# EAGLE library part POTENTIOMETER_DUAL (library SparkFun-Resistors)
Potentiometer (Pot) Dual-Gang Three-terminal potentiometers, with an adjustable wiper and two adjustable resistors. A pot can be used to create a configurable voltage divider, or as a variable resistor. This is a dua-gang pot - it includes two separate circuits, both controlled by one wiper. Variants PTH-12MM and PTH-12MM-KIT - 12mm Square, PTH Vertical Pots Used on the SparkFun SparkPunk Sound Kit (filter control) The KIT variant exposes copper on only one side of the PTH pad, so the part can only be assembled on one side of the PCB. Useful for beginner soldering kits.

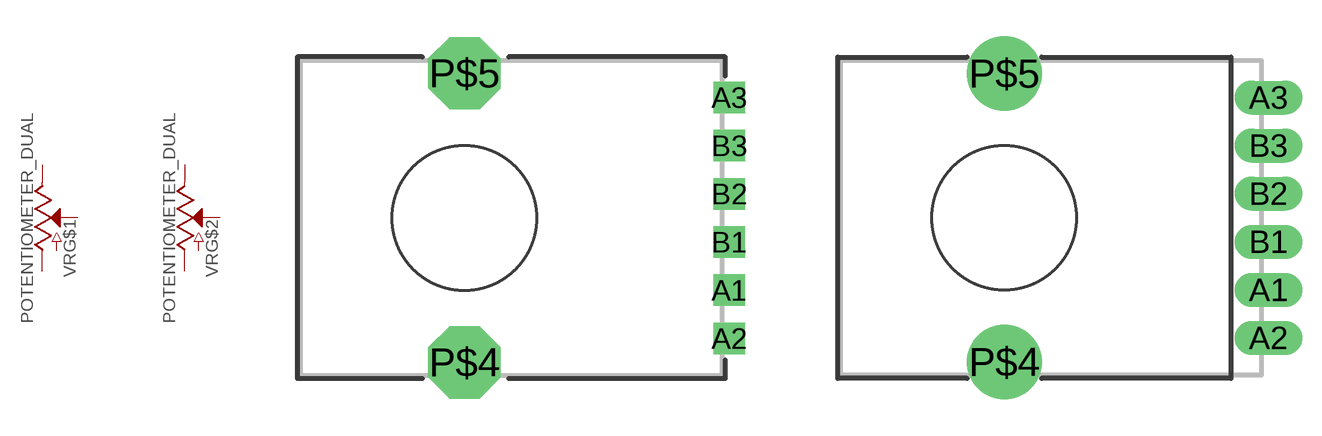
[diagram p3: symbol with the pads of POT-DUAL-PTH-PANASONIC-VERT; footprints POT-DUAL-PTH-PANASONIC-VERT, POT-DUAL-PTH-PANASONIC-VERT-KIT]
Designator prefix VR; gates G$1=POTENTIOMETER G$2=POTENTIOMETER

## POTENTIOMETER_DUAL-PTH-12MM-1/20W-20% (PROD_ID: RES-11897)  [POT-DUAL-PTH-PANASONIC-VERT]
A1  G$1:E  pas
A2  G$1:S  pas
A3  G$1:A  pas
B1  G$2:E  pas
B2  G$2:S  pas
B3  G$2:A  pas

## POTENTIOMETER_DUAL-PTH-12MM-1/20W-20%-KIT (PROD_ID: RES-11897)  [POT-DUAL-PTH-PANASONIC-VERT-KIT]
Pads as for POT-DUAL-PTH-PANASONIC-VERT

## Footprint POT-DUAL-PTH-PANASONIC-VERT (pad centres in mm)
Panasonic Dual-Gang 12mm PTH Potentiometer Datasheet (Fits EVJY-00, EVJY-80, EVJY-81, EVJY-10, etc)
drill 0.8 square: A1 11,-3; A2 11,-5; A3 11,5; B1 11,-1; B2 11,1; B3 11,3
drill 2 octagon: P$4 0,-6; P$5 0,6

## Footprint POT-DUAL-PTH-PANASONIC-VERT-KIT (pad centres in mm)
Panasonic Dual-Gang 12mm PTH Potentiometer (KIT Variant) Warning: This is the KIT version of this package. This package has a smaller diameter top stop mask, which doesn't cover the diameter of the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
drill 0.9 long: A1 11,-3; A2 11,-5; A3 11,5; B1 11,-1; B2 11,1; B3 11,3
drill 2.1: P$4 0,-6; P$5 0,6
